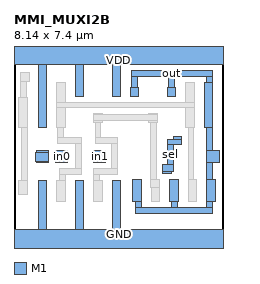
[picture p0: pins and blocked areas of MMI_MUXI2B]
MACRO MMI_MUXI2B
	CLASS CORE ;
	FOREIGN MMI_MUXI2B 0 0 ;
	SIZE 8.14 BY 7.4 ;
	SYMMETRY X Y ;
	SITE CORE1 ;
	PIN out
		DIRECTION output ;
		USE SIGNAL ;
		PORT
			LAYER M1 ;
			RECT 4.57 6.44 7.73 6.67 ;
			LAYER M1 ;
			RECT 4.57 6.02 4.8 6.44 ;
			LAYER M1 ;
			RECT 6.01 6.025 6.24 6.44 ;
			LAYER M1 ;
			RECT 7.5 6.21 7.73 6.44 ;
			LAYER M1 ;
			RECT 4.52 5.68 4.86 6.02 ;
			LAYER M1 ;
			RECT 5.96 5.685 6.3 6.025 ;
			LAYER M1 ;
			RECT 7.4 4.45 7.74 6.21 ;
			LAYER M1 ;
			RECT 7.5 3.555 7.73 4.45 ;
			LAYER M1 ;
			RECT 7.5 3.105 7.995 3.555 ;
			LAYER M1 ;
			RECT 7.5 2.415 7.73 3.105 ;
			LAYER M1 ;
			RECT 4.62 1.575 4.96 2.415 ;
			LAYER M1 ;
			RECT 6.06 1.575 6.4 2.415 ;
			LAYER M1 ;
			RECT 7.5 1.575 7.84 2.415 ;
			LAYER M1 ;
			RECT 4.73 1.345 4.96 1.575 ;
			LAYER M1 ;
			RECT 6.12 1.345 6.35 1.575 ;
			LAYER M1 ;
			RECT 7.5 1.345 7.73 1.575 ;
			LAYER M1 ;
			RECT 4.73 1.115 7.73 1.345 ;
		END
		AntennaDiffArea 4.14 ;
	END out
	PIN in1
		DIRECTION input ;
		USE SIGNAL ;
		PORT
			LAYER M1 ;
			RECT 3.105 3.105 3.555 3.555 ;
		END
		AntennaGateArea 0.9936 ;
	END in1
	PIN sel
		DIRECTION input ;
		USE SIGNAL ;
		PORT
			LAYER M1 ;
			RECT 6.2 4.01 6.54 4.12 ;
			LAYER M1 ;
			RECT 5.985 3.78 6.54 4.01 ;
			LAYER M1 ;
			RECT 0.885 3.48 1.335 3.555 ;
			LAYER M1 ;
			RECT 0.82 3.14 1.335 3.48 ;
			LAYER M1 ;
			RECT 0.885 3.105 1.335 3.14 ;
			LAYER M1 ;
			RECT 5.985 3.005 6.215 3.78 ;
			LAYER M1 ;
			RECT 5.78 2.735 6.215 3.005 ;
			LAYER M1 ;
			RECT 5.78 2.665 6.12 2.735 ;
		END
		AntennaGateArea 1.3284 ;
	END sel
	PIN GND
		DIRECTION inout ;
		USE GROUND ;
		PORT
			LAYER M1 ;
			RECT 0.94 0.5 1.28 2.4 ;
			LAYER M1 ;
			RECT 2.38 0.5 2.72 2.4 ;
			LAYER M1 ;
			RECT 3.82 0.5 4.16 2.4 ;
			LAYER M1 ;
			RECT 0 -0.5 8.14 0.5 ;
		END
	END GND
	PIN VDD
		DIRECTION inout ;
		USE POWER ;
		PORT
			LAYER M1 ;
			RECT 0 6.9 8.14 7.9 ;
			LAYER M1 ;
			RECT 0.94 4.45 1.28 6.9 ;
			LAYER M1 ;
			RECT 2.38 5.68 2.72 6.9 ;
			LAYER M1 ;
			RECT 3.82 5.68 4.16 6.9 ;
		END
	END VDD
	PIN in0
		DIRECTION input ;
		USE SIGNAL ;
		PORT
			LAYER M1 ;
			RECT 1.625 3.105 2.075 3.555 ;
		END
		AntennaGateArea 0.9936 ;
	END in0
	OBS
		LAYER M1 ;
		RECT 0.26 6.25 0.6 6.59 ;
		LAYER M1 ;
		RECT 0.26 5.61 0.49 6.25 ;
		LAYER M1 ;
		RECT 0.18 4.45 0.52 5.61 ;
		LAYER M1 ;
		RECT 1.66 5.45 2 6.21 ;
		LAYER M1 ;
		RECT 6.68 5.45 7.02 6.21 ;
		LAYER M1 ;
		RECT 1.66 5.22 7.02 5.45 ;
		LAYER M1 ;
		RECT 1.66 4.45 2 5.22 ;
		LAYER M1 ;
		RECT 3.1 4.955 3.44 4.99 ;
		LAYER M1 ;
		RECT 5.24 4.955 5.58 4.99 ;
		LAYER M1 ;
		RECT 3.1 4.725 5.58 4.955 ;
		LAYER M1 ;
		RECT 3.1 4.65 3.44 4.725 ;
		LAYER M1 ;
		RECT 5.24 4.65 5.58 4.725 ;
		LAYER M1 ;
		RECT 0.29 2.4 0.52 4.45 ;
		LAYER M1 ;
		RECT 1.71 4.065 1.94 4.45 ;
		LAYER M1 ;
		RECT 3.155 4.065 3.385 4.65 ;
		LAYER M1 ;
		RECT 1.71 3.835 2.63 4.065 ;
		LAYER M1 ;
		RECT 3.155 3.835 4.035 4.065 ;
		LAYER M1 ;
		RECT 2.4 2.865 2.63 3.835 ;
		LAYER M1 ;
		RECT 3.805 2.87 4.035 3.835 ;
		LAYER M1 ;
		RECT 1.77 2.635 2.63 2.865 ;
		LAYER M1 ;
		RECT 3.105 2.64 4.035 2.87 ;
		LAYER M1 ;
		RECT 1.77 2.4 2 2.635 ;
		LAYER M1 ;
		RECT 3.105 2.4 3.335 2.64 ;
		LAYER M1 ;
		RECT 5.315 2.415 5.545 4.65 ;
		LAYER M1 ;
		RECT 6.68 4.45 7.02 5.22 ;
		LAYER M1 ;
		RECT 6.78 2.415 7.01 4.45 ;
		LAYER M1 ;
		RECT 0.18 1.86 0.52 2.4 ;
		LAYER M1 ;
		RECT 1.66 1.56 2 2.4 ;
		LAYER M1 ;
		RECT 3.1 1.56 3.44 2.4 ;
		LAYER M1 ;
		RECT 5.315 2.13 5.68 2.415 ;
		LAYER M1 ;
		RECT 5.34 1.575 5.68 2.13 ;
		LAYER M1 ;
		RECT 6.78 1.575 7.12 2.415 ;
	END
END MMI_MUXI2B
